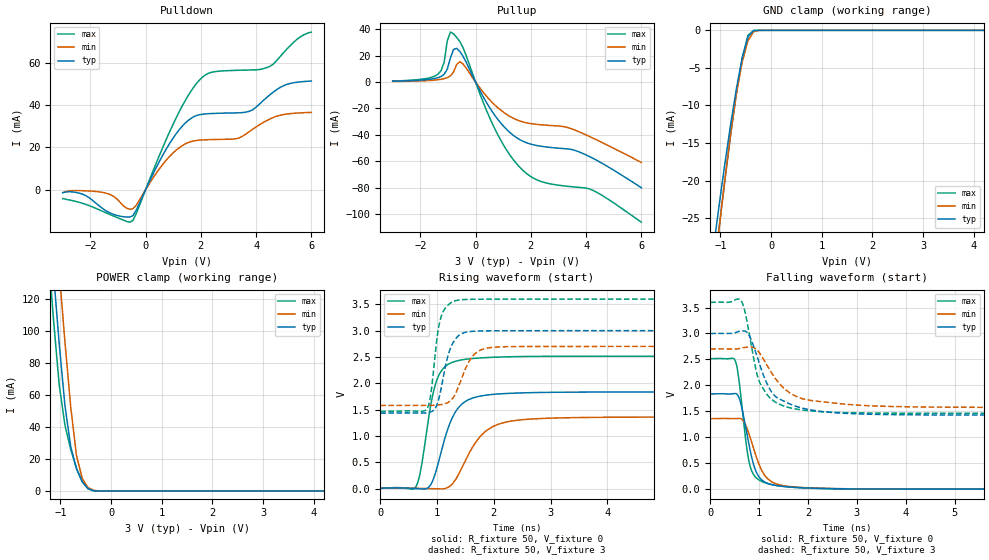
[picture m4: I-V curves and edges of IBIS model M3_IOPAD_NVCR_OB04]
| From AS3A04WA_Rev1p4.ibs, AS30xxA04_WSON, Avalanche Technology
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[Model] M3_IOPAD_NVCR_OB04
Model_type I/O
Enable   Active-High
Vinl  =  0.9
Vinh  =  2.1
Vmeas =  1.5
Cref  =  30e-12
| Capacitance  typ   min   max
C_comp   3.872127e-12   3.590660e-12   4.190515e-12
| Variables   typ   min   max
[GND Clamp Reference]   0   0   0
[POWER Clamp Reference]   3   2.7   3.6
[Pulldown Reference]   0   0   0
[Pullup Reference]   3   2.7   3.6
[Temperature Range]   25   125   -40
[Voltage Range]   3   2.7   3.6
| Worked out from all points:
|   slope of the pulldown table from 0 to 0.45 V, typ, clamps not added: 37.1 ohm
|   slope of the pullup table from 0 to 0.45 V, typ, clamps not added: 25.9 ohm
|   GND clamp passes 1 mA (typ) near -0.46 V on its own axis
|   POWER clamp passes 1 mA (typ) near -0.42 V on its own axis
|   falling waveform, R_fixture 50, V_fixture 0: 20-80 % time 256ps typ, 326ps min, 201ps max; typ from 1.83 V to 0 V
|   falling waveform, R_fixture 50, V_fixture 3: 20-80 % time 490ps typ, 623ps min, 350ps max; typ from 3 V to 1.43 V
|   rising waveform, R_fixture 50, V_fixture 0: 20-80 % time 339ps typ, 474ps min, 243ps max; typ from 0 V to 1.83 V
|   rising waveform, R_fixture 50, V_fixture 3: 20-80 % time 204ps typ, 275ps min, 147ps max; typ from 1.43 V to 3 V
[GND Clamp]
| Voltage   I(typ)   I(min)   I(max)
-3V       -145.9mA   -153.7mA   -144.2mA
-1.138V   -29.07mA   -33.2mA    -32.68mA
-1.024V   -23.24mA   -26.38mA   -26.15mA
-910.3mV  -17.69mA   -19.83mA   -19.83mA
-796.6mV  -12.47mA   -13.74mA   -13.82mA
-682.8mV  -7.718mA   -8.413mA   -8.316mA
-569mV    -3.663mA   -4.215mA   -3.675mA
-455.2mV  -839.2uA   -1.36mA    -666.1uA
-341.4mV  -35.63uA   -163.9uA   -11.17uA
-113.8mV  -8.642nA   -411.9nA   -1.888nA
6V        0A         0A         0A
[POWER Clamp]
| Voltage   I(typ)   I(min)   I(max)
-3V       949.8mA    993.3mA    923.5mA
-1.252V   183.6mA    231.1mA    154mA
-1.138V   136.7mA    183.8mA    107.6mA
-1.024V   92.09mA    137.6mA    66.35mA
-910.3mV  53.33mA    93.06mA    41.06mA
-796.6mV  27.72mA    52.58mA    25.94mA
-682.8mV  13.75mA    22.15mA    14.29mA
-569mV    5.664mA    7.785mA    5.738mA
-455.2mV  1.446mA    2.116mA    1.305mA
-341.4mV  77.09uA    373.9uA    62.73uA
-227.6mV  1.148uA    21.11uA    332nA
6V        0A         0A         0A
[Pulldown]
| Voltage   I(typ)   I(min)   I(max)
-3V       -1.433mA   -1.306mA   -4.157mA
-2.276V   -2.108mA   -451.4uA   -6.425mA
-1.479V   -9.535mA   -1.453mA   -10.63mA
-455.2mV  -12.21mA   -8.895mA   -14.49mA
931mV     23.15mA    16.61mA    29.13mA
1.448V    31.69mA    21.77mA    42.45mA
1.966V    35.52mA    23.49mA    52.07mA
2.483V    36.1mA     23.77mA    55.8mA
3.745V    37.06mA    27.41mA    56.63mA
4.49V     44.79mA    33.42mA    58.29mA
5.11V     49.81mA    35.81mA    66.46mA
6V        51.42mA    36.59mA    74.56mA
[Pullup]
| Voltage   I(typ)   I(min)   I(max)
-3V       653.5uA    465.2uA    766.8uA
-1.366V   3.311mA    1.742mA    5.899mA
-1.138V   5.906mA    2.581mA    14.98mA
-1.024V   9.73mA     3.378mA    31.24mA
-910.3mV  18.3mA     4.722mA    37.88mA
-796.6mV  24.73mA    7.691mA    36.53mA
-455.2mV  19.63mA    13.8mA     26.19mA
620.7mV   -22.92mA   -15.8mA    -32.1mA
1.655V    -44.22mA   -29.83mA   -65.72mA
2.379V    -48.66mA   -32.38mA   -75.39mA
3.745V    -52.9mA    -37.67mA   -79.8mA
6V        -80.07mA   -60.91mA   -106.2mA
[Ramp]
dV/dt_r   1.10101/0.339017n  0.814816/0.474352n  1.50845/0.242789n
dV/dt_f   0.94313/0.490001n  0.674772/0.62293n  1.28285/0.349771n
R_load = 50
[Falling Waveform]
R_fixture = 50
V_fixture = 0
V_fixture_min = 0
V_fixture_max = 0
| Time   V(typ)   V(min)   V(max)
0s        1.835V     1.358V     2.514V
508.1ps   1.842V     1.359V     2.484V
563ps     1.81V      1.364V     2.266V
628.4ps   1.639V     1.356V     1.772V
754.2ps   1.042V     1.168V     742mV
850.8ps   600.9mV    893.8mV    345.7mV
956.7ps   299.5mV    582.8mV    204.1mV
1.113ns   137.2mV    268.9mV    125.8mV
1.514ns   51.15mV    64.98mV    51.11mV
21.88ns   622.8nV    1.219uV    10.89uV
[Falling Waveform]
R_fixture = 50
V_fixture = 3
V_fixture_min = 2.7
V_fixture_max = 3.6
| Time   V(typ)   V(min)   V(max)
0s        3V         2.7V       3.6V
624.2ps   3.048V     2.716V     3.642V
788.3ps   2.977V     2.74V      3.046V
963.4ps   2.539V     2.676V     2.19V
1.115ns   2.134V     2.463V     1.888V
1.348ns   1.775V     2.113V     1.67V
1.624ns   1.645V     1.858V     1.571V
2.036ns   1.53V      1.713V     1.509V
4.44ns    1.431V     1.582V     1.463V
21.88ns   1.428V     1.575V     1.462V
[Rising Waveform]
R_fixture = 50
V_fixture = 0
V_fixture_min = 0
V_fixture_max = 0
| Time   V(typ)   V(min)   V(max)
0s        414.5nV    971.2nV    10.8uV
619.8ps   -611.3uV   5.171mV    21.45mV
717.4ps   -8.991mV   2.855mV    378.7mV
871ps     45.71mV    -2.403mV   1.477V
1.013ns   453.4mV    -7.701mV   2.11V
1.262ns   1.331V     79.29mV    2.395V
1.571ns   1.696V     685.2mV    2.465V
2.049ns   1.795V     1.209V     2.497V
3.034ns   1.828V     1.339V     2.512V
21.88ns   1.835V     1.358V     2.514V
[Rising Waveform]
R_fixture = 50
V_fixture = 3
V_fixture_min = 2.7
V_fixture_max = 3.6
| Time   V(typ)   V(min)   V(max)
0s        1.428V     1.575V     1.462V
810.7ps   1.438V     1.579V     1.497V
887.5ps   1.456V     1.579V     1.779V
1.003ns   1.607V     1.585V     2.894V
1.068ns   1.883V     1.594V     3.253V
1.21ns    2.592V     1.647V     3.502V
1.401ns   2.923V     2.001V     3.585V
1.655ns   2.99V      2.55V      3.596V
2.116ns   2.998V     2.692V     3.599V
21.88ns   3V         2.7V       3.6V
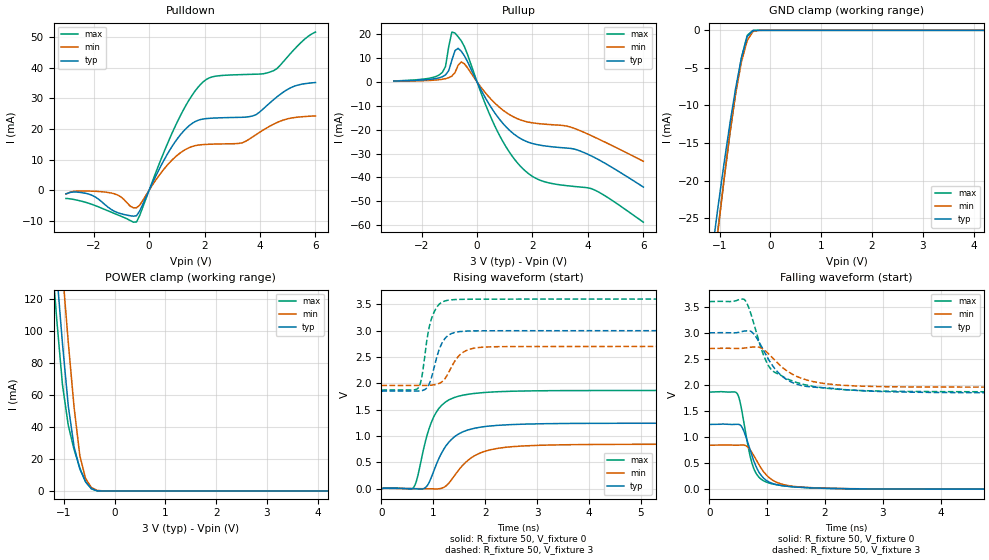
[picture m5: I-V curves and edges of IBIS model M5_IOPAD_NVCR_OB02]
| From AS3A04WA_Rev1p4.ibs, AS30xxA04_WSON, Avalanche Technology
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[Model] M5_IOPAD_NVCR_OB02
Model_type I/O
Enable   Active-High
Vinl  =  0.9
Vinh  =  2.1
Vmeas =  1.5
Cref  =  30e-12
| Capacitance  typ   min   max
C_comp   3.872127e-12   3.590660e-12   4.190515e-12
| Variables   typ   min   max
[GND Clamp Reference]   0   0   0
[POWER Clamp Reference]   3   2.7   3.6
[Pulldown Reference]   0   0   0
[Pullup Reference]   3   2.7   3.6
[Temperature Range]   25   125   -40
[Voltage Range]   3   2.7   3.6
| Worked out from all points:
|   slope of the pulldown table from 0 to 0.45 V, typ, clamps not added: 53.8 ohm
|   slope of the pullup table from 0 to 0.45 V, typ, clamps not added: 46.8 ohm
|   GND clamp passes 1 mA (typ) near -0.46 V on its own axis
|   POWER clamp passes 1 mA (typ) near -0.42 V on its own axis
|   falling waveform, R_fixture 50, V_fixture 0: 20-80 % time 272ps typ, 348ps min, 213ps max; typ from 1.24 V to 0 V
|   falling waveform, R_fixture 50, V_fixture 3: 20-80 % time 489ps typ, 589ps min, 431ps max; typ from 3 V to 1.85 V
|   rising waveform, R_fixture 50, V_fixture 0: 20-80 % time 445ps typ, 548ps min, 354ps max; typ from 0 V to 1.24 V
|   rising waveform, R_fixture 50, V_fixture 3: 20-80 % time 215ps typ, 288ps min, 179ps max; typ from 1.85 V to 3 V
[GND Clamp]
| Voltage   I(typ)   I(min)   I(max)
-3V       -145.9mA   -153.7mA   -144.2mA
-1.138V   -29.07mA   -33.2mA    -32.68mA
-1.024V   -23.24mA   -26.38mA   -26.15mA
-910.3mV  -17.69mA   -19.83mA   -19.83mA
-796.6mV  -12.47mA   -13.74mA   -13.82mA
-682.8mV  -7.718mA   -8.413mA   -8.316mA
-569mV    -3.663mA   -4.215mA   -3.675mA
-455.2mV  -839.2uA   -1.36mA    -666.1uA
-341.4mV  -35.63uA   -163.9uA   -11.17uA
-113.8mV  -8.642nA   -411.9nA   -1.888nA
6V        0A         0A         0A
[POWER Clamp]
| Voltage   I(typ)   I(min)   I(max)
-3V       949.8mA    993.3mA    923.5mA
-1.252V   183.6mA    231.1mA    154mA
-1.138V   136.7mA    183.8mA    107.6mA
-1.024V   92.09mA    137.6mA    66.35mA
-910.3mV  53.33mA    93.06mA    41.06mA
-796.6mV  27.72mA    52.58mA    25.94mA
-682.8mV  13.75mA    22.15mA    14.29mA
-569mV    5.664mA    7.785mA    5.738mA
-455.2mV  1.446mA    2.116mA    1.305mA
-341.4mV  77.09uA    373.9uA    62.73uA
-227.6mV  1.148uA    21.11uA    332nA
6V        0A         0A         0A
[Pulldown]
| Voltage   I(typ)   I(min)   I(max)
-3V       -1.234mA   -1.249mA   -2.704mA
-2.162V   -1.332mA   -302.4uA   -4.325mA
-1.366V   -6.313mA   -938uA     -7.187mA
-455.2mV  -8.34mA    -5.727mA   -10.36mA
931mV     15.68mA    10.73mA    20.66mA
1.862V    23.06mA    14.81mA    34.56mA
2.379V    23.54mA    15.04mA    37.15mA
3.248V    23.75mA    15.26mA    37.67mA
3.745V    24.23mA    17.44mA    37.79mA
4.49V     29.51mA    21.52mA    38.97mA
5.234V    33.9mA     23.67mA    45.9mA
6V        35.1mA     24.21mA    51.55mA
[Pullup]
| Voltage   I(typ)   I(min)   I(max)
-3V       346.1uA    246.7uA    405.8uA
-1.366V   1.712mA    917.3uA    2.902mA
-1.138V   2.946mA    1.348mA    6.431mA
-910.3mV  9.029mA    2.421mA    20.86mA
-796.6mV  13.11mA    3.887mA    20.47mA
-455.2mV  10.88mA    7.554mA    14.73mA
620.7mV   -12.67mA   -8.642mA   -17.98mA
1.655V    -24.29mA   -16.27mA   -36.41mA
2.379V    -26.71mA   -17.65mA   -41.63mA
3.745V    -29.06mA   -20.57mA   -44.07mA
4.366V    -32.46mA   -23.84mA   -46.01mA
6V        -44.07mA   -33.25mA   -58.77mA
[Ramp]
dV/dt_r   0.745426/0.445098n  0.505855/0.548119n  1.11854/0.354104n
dV/dt_f   0.690854/0.488836n  0.446189/0.588493n  1.0388/0.430793n
R_load = 50
[Falling Waveform]
R_fixture = 50
V_fixture = 0
V_fixture_min = 0
V_fixture_max = 0
| Time   V(typ)   V(min)   V(max)
0s        1.242V     843.1mV    1.864V
484ps     1.245V     843.3mV    1.83V
528.7ps   1.234V     845.6mV    1.686V
581ps     1.155V     847.2mV    1.385V
680.5ps   835.3mV    790.2mV    759.3mV
731.6ps   658.4mV    713.3mV    517.2mV
861.2ps   320.3mV    463.9mV    224.8mV
1.118ns   100.1mV    156.7mV    94.08mV
1.479ns   41.98mV    51.06mV    43.89mV
21.88ns   454.8nV    1.105uV    9.58uV
[Falling Waveform]
R_fixture = 50
V_fixture = 3
V_fixture_min = 2.7
V_fixture_max = 3.6
| Time   V(typ)   V(min)   V(max)
0s        3V         2.7V       3.6V
602.4ps   3.033V     2.707V     3.641V
664.5ps   3.038V     2.718V     3.533V
768.8ps   2.978V     2.728V     3.179V
937.9ps   2.663V     2.68V      2.571V
1.098ns   2.363V     2.513V     2.267V
1.48ns    2.025V     2.18V      2.058V
2.181ns   1.927V     2.004V     1.92V
4.854ns   1.85V      1.958V     1.869V
21.88ns   1.849V     1.956V     1.869V
[Rising Waveform]
R_fixture = 50
V_fixture = 0
V_fixture_min = 0
V_fixture_max = 0
| Time   V(typ)   V(min)   V(max)
0s        358.1nV    978.1nV    9.504uV
603.6ps   -717.2uV   2.684mV    6.795mV
687.9ps   -5.652mV   1.629mV    190.4mV
864.1ps   34.46mV    -2.283mV   958.5mV
982.8ps   267.3mV    -5.674mV   1.309V
1.105ns   566.1mV    -3.235mV   1.52V
1.4ns     978.5mV    235.5mV    1.728V
1.905ns   1.167V     676.7mV    1.82V
3.793ns   1.239V     836.4mV    1.863V
21.88ns   1.242V     843.1mV    1.864V
[Rising Waveform]
R_fixture = 50
V_fixture = 3
V_fixture_min = 2.7
V_fixture_max = 3.6
| Time   V(typ)   V(min)   V(max)
0s        1.849V     1.956V     1.869V
723.2ps   1.854V     1.959V     1.929V
790.5ps   1.864V     1.959V     2.187V
875.7ps   1.911V     1.959V     2.819V
989ps     2.199V     1.969V     3.295V
1.155ns   2.741V     2.02V      3.533V
1.4ns     2.962V     2.399V     3.59V
1.68ns    2.993V     2.641V     3.597V
2.276ns   2.998V     2.696V     3.599V
21.88ns   3V         2.7V       3.6V
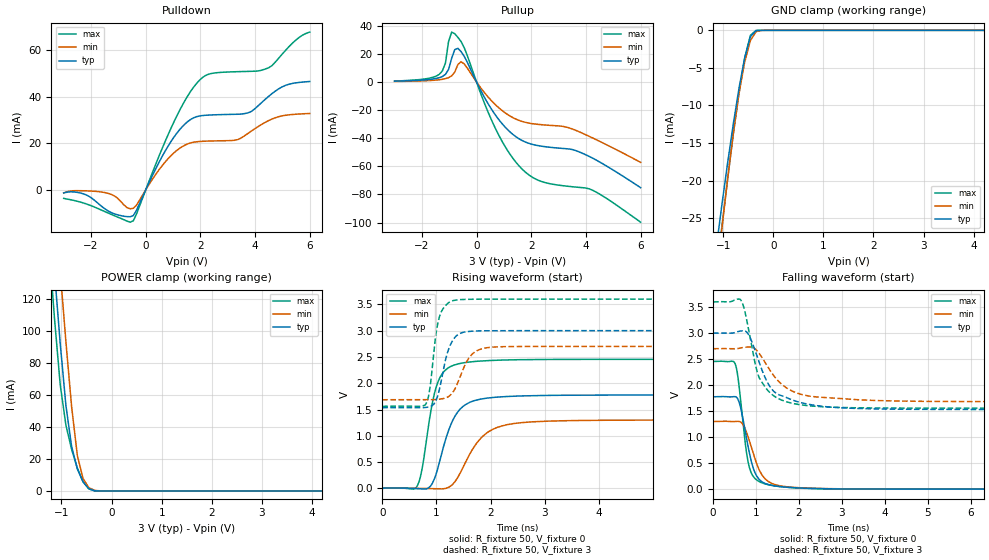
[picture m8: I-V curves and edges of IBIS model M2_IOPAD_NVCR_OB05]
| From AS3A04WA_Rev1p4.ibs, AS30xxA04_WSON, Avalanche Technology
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[Model] M2_IOPAD_NVCR_OB05
Model_type I/O
Enable   Active-High
Vinl  =  0.9
Vinh  =  2.1
Vmeas =  1.5
Cref  =  30e-12
| Capacitance  typ   min   max
C_comp   3.872127e-12   3.590660e-12   4.190515e-12
| Variables   typ   min   max
[GND Clamp Reference]   0   0   0
[POWER Clamp Reference]   3   2.7   3.6
[Pulldown Reference]   0   0   0
[Pullup Reference]   3   2.7   3.6
[Temperature Range]   25   125   -40
[Voltage Range]   3   2.7   3.6
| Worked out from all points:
|   slope of the pulldown table from 0 to 0.45 V, typ, clamps not added: 40.8 ohm
|   slope of the pullup table from 0 to 0.45 V, typ, clamps not added: 27.6 ohm
|   GND clamp passes 1 mA (typ) near -0.46 V on its own axis
|   POWER clamp passes 1 mA (typ) near -0.42 V on its own axis
|   falling waveform, R_fixture 50, V_fixture 0: 20-80 % time 277ps typ, 350ps min, 216ps max; typ from 1.78 V to 0 V
|   falling waveform, R_fixture 50, V_fixture 3: 20-80 % time 546ps typ, 675ps min, 412ps max; typ from 3 V to 1.53 V
|   rising waveform, R_fixture 50, V_fixture 0: 20-80 % time 352ps typ, 489ps min, 252ps max; typ from 0 V to 1.78 V
|   rising waveform, R_fixture 50, V_fixture 3: 20-80 % time 207ps typ, 274ps min, 149ps max; typ from 1.53 V to 3 V
[GND Clamp]
| Voltage   I(typ)   I(min)   I(max)
-3V       -145.9mA   -153.7mA   -144.2mA
-1.138V   -29.07mA   -33.2mA    -32.68mA
-1.024V   -23.24mA   -26.38mA   -26.15mA
-910.3mV  -17.69mA   -19.83mA   -19.83mA
-796.6mV  -12.47mA   -13.74mA   -13.82mA
-682.8mV  -7.718mA   -8.413mA   -8.316mA
-569mV    -3.663mA   -4.215mA   -3.675mA
-455.2mV  -839.2uA   -1.36mA    -666.1uA
-341.4mV  -35.63uA   -163.9uA   -11.17uA
-113.8mV  -8.642nA   -411.9nA   -1.888nA
6V        0A         0A         0A
[POWER Clamp]
| Voltage   I(typ)   I(min)   I(max)
-3V       949.8mA    993.3mA    923.5mA
-1.252V   183.6mA    231.1mA    154mA
-1.138V   136.7mA    183.8mA    107.6mA
-1.024V   92.09mA    137.6mA    66.35mA
-910.3mV  53.33mA    93.06mA    41.06mA
-796.6mV  27.72mA    52.58mA    25.94mA
-682.8mV  13.75mA    22.15mA    14.29mA
-569mV    5.664mA    7.785mA    5.738mA
-455.2mV  1.446mA    2.116mA    1.305mA
-341.4mV  77.09uA    373.9uA    62.73uA
-227.6mV  1.148uA    21.11uA    332nA
6V        0A         0A         0A
[Pulldown]
| Voltage   I(typ)   I(min)   I(max)
-3V       -1.372mA   -1.292mA   -3.673mA
-2.276V   -1.719mA   -395.8uA   -5.658mA
-1.479V   -8.289mA   -1.203mA   -9.431mA
-455.2mV  -11.08mA   -7.932mA   -13.32mA
931mV     20.94mA    14.81mA    26.71mA
1.448V    28.51mA    19.34mA    38.71mA
1.966V    31.8mA     20.82mA    47.19mA
3.248V    32.52mA    21.34mA    50.83mA
3.745V    33.17mA    24.34mA    51mA
4.49V     40.2mA     29.79mA    52.52mA
5.11V     44.97mA    32.1mA     60mA
6V        46.63mA    32.88mA    67.91mA
[Pullup]
| Voltage   I(typ)   I(min)   I(max)
-3V       614uA      436.7uA    721uA
-1.366V   3.083mA    1.626mA    5.453mA
-1.138V   5.465mA    2.405mA    13.53mA
-1.024V   8.949mA    3.144mA    28.86mA
-910.3mV  16.94mA    4.386mA    35.55mA
-796.6mV  23.1mA     7.129mA    34.34mA
-455.2mV  18.43mA    12.94mA    24.63mA
620.7mV   -21.52mA   -14.81mA   -30.19mA
1.655V    -41.5mA    -27.97mA   -61.73mA
2.379V    -45.66mA   -30.35mA   -70.78mA
3.745V    -49.64mA   -35.32mA   -74.93mA
6V        -75.17mA   -57.13mA   -99.72mA
[Ramp]
dV/dt_r   1.06555/0.352337n  0.780363/0.489275n  1.47276/0.251554n
dV/dt_f   0.880737/0.545815n  0.610248/0.674994n  1.22549/0.411725n
R_load = 50
[Falling Waveform]
R_fixture = 50
V_fixture = 0
V_fixture_min = 0
V_fixture_max = 0
| Time   V(typ)   V(min)   V(max)
0s        1.776V     1.301V     2.455V
505.8ps   1.78V      1.3V       2.427V
560.1ps   1.754V     1.304V     2.26V
632ps     1.602V     1.295V     1.785V
766.5ps   1.037V     1.121V     776.8mV
871.8ps   600.6mV    859.9mV    351.1mV
977.7ps   314.6mV    580.4mV    203.6mV
1.137ns   143.5mV    277.9mV    122.8mV
1.508ns   54.5mV     73.06mV    53.78mV
21.88ns   526.5nV    1.138uV    10.53uV
[Falling Waveform]
R_fixture = 50
V_fixture = 3
V_fixture_min = 2.7
V_fixture_max = 3.6
| Time   V(typ)   V(min)   V(max)
0s        3V         2.7V       3.6V
642.3ps   3.04V      2.715V     3.64V
727.5ps   3.044V     2.727V     3.464V
833ps     2.964V     2.734V     3.046V
1.007ns   2.601V     2.677V     2.32V
1.111ns   2.354V     2.567V     2.087V
1.462ns   1.848V     2.132V     1.768V
2.242ns   1.63V      1.79V      1.602V
5.343ns   1.533V     1.686V     1.558V
21.88ns   1.532V     1.683V     1.558V
[Rising Waveform]
R_fixture = 50
V_fixture = 0
V_fixture_min = 0
V_fixture_max = 0
| Time   V(typ)   V(min)   V(max)
0s        399.8nV    962nV      10.49uV
628.9ps   -2.765mV   3.122mV    19.82mV
737.1ps   -10.94mV   970.1uV    384.9mV
883.7ps   37.77mV    -3.381mV   1.395V
1.032ns   408.5mV    -8.794mV   2.035V
1.295ns   1.284V     74.64mV    2.333V
1.577ns   1.617V     582.3mV    2.4V
2.025ns   1.728V     1.117V     2.434V
2.964ns   1.767V     1.276V     2.452V
21.88ns   1.776V     1.301V     2.455V
[Rising Waveform]
R_fixture = 50
V_fixture = 3
V_fixture_min = 2.7
V_fixture_max = 3.6
| Time   V(typ)   V(min)   V(max)
0s        1.532V     1.683V     1.558V
801ps     1.539V     1.685V     1.6V
866.1ps   1.552V     1.685V     1.819V
986.3ps   1.66V      1.689V     2.905V
1.058ns   1.899V     1.697V     3.273V
1.221ns   2.638V     1.746V     3.528V
1.424ns   2.94V      2.088V     3.589V
1.668ns   2.99V      2.562V     3.597V
2.168ns   2.998V     2.693V     3.599V
21.88ns   3V         2.7V       3.6V
